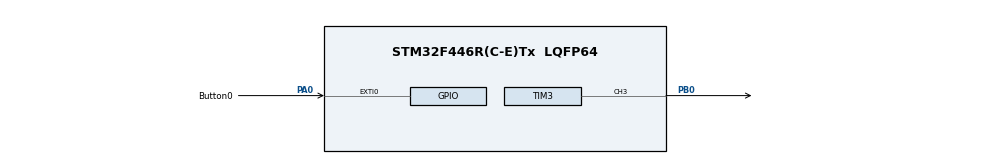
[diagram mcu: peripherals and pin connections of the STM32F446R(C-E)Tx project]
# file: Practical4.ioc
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Dma.Request0=TIM2_CH1
Dma.TIM2_CH1.0.Direction=DMA_PERIPH_TO_MEMORY
Dma.TIM2_CH1.0.FIFOMode=DMA_FIFOMODE_DISABLE
Dma.TIM2_CH1.0.Instance=DMA1_Stream5
Dma.TIM2_CH1.0.MemDataAlignment=DMA_MDATAALIGN_WORD
Dma.TIM2_CH1.0.MemInc=DMA_MINC_ENABLE
Dma.TIM2_CH1.0.Mode=DMA_NORMAL
Dma.TIM2_CH1.0.PeriphDataAlignment=DMA_PDATAALIGN_WORD
Dma.TIM2_CH1.0.PeriphInc=DMA_PINC_DISABLE
Dma.TIM2_CH1.0.Priority=DMA_PRIORITY_LOW
Mcu.Family=STM32F4
Mcu.Name=STM32F446R(C-E)Tx
Mcu.Package=LQFP64
NVIC.DMA1_Stream5_IRQn=true\:0\:0\:false\:false\:true\:false\:true\:true
NVIC.PriorityGroup=NVIC_PRIORITYGROUP_4
PA0-WKUP.GPIO_Label=Button0
PA0-WKUP.Signal=GPXTI0
PB0.Signal=S_TIM3_CH3
PH0-OSC_IN.Mode=HSE-External-Oscillator
PH0-OSC_IN.Signal=RCC_OSC_IN
PH1-OSC_OUT.Mode=HSE-External-Oscillator
PH1-OSC_OUT.Signal=RCC_OSC_OUT
ProjectManager.HeapSize=0x200
ProjectManager.StackSize=0x400
ProjectManager.TargetToolchain=STM32CubeIDE
RCC.CortexFreq_Value=16000000
RCC.USBFreq_Value=96000000
RCC.VCOOutputFreq_Value=192000000
SH.S_TIM3_CH3.0=TIM3_CH3,PWM Generation3 CH3
TIM2.Channel-Output\ Compare1\ No\ Output=TIM_CHANNEL_1
TIM3.Channel-PWM\ Generation3\ CH3=TIM_CHANNEL_3
TIM3.Period=159
VP_TIM2_VS_ClockSourceINT.Mode=Internal
VP_TIM2_VS_no_output1.Mode=Output Compare1 No Output
VP_TIM3_VS_ClockSourceINT.Mode=Internal
board=custom

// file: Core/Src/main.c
/* USER CODE BEGIN Header */
/**
  ******************************************************************************
  * @file           : main.c
  * @brief          : Main program body
  ******************************************************************************
  * @attention
  *
  * Copyright (c) 2025 STMicroelectronics.
  * All rights reserved.
  *
  * This software is licensed under terms that can be found in the LICENSE file
  * in the root directory of this software component.
  * If no LICENSE file comes with this software, it is provided AS-IS.
  *
  ******************************************************************************
  */
/* USER CODE END Header */
#include "main.h"

/* USER CODE BEGIN Includes */
#include <stdio.h>
#include <stdint.h>
#include "stm32f4xx.h"
#include "lcd_stm32f4.h"

//INCLUDE LUTS

//Following three have 75000 samples from their respective .wav audio file.
//So when playing back the samples, to effectively reproduce the original file the play back frequency should be (selected samples)/(total file samples) * sampling_freq

//Drum.wav Duration       : 00:00:11.34 = 499968 samples
#include "drum.inc"

//Guitar.wav Duration       : 00:00:10.58 = 466560 samples = 793.469 CDDA sector
#include "guitar.inc"

//Piano.wav Duration       : 00:00:18.86 = 831744 samples = 1414.53 CDDA sectors
#include "piano.inc"

//Following three have 128 samples, we will play them back at 500Hz, meaning a play back sample rate of 64kHz.
#include "saw.inc"
#include "sine.inc"
#include "triangle.inc"

/* USER CODE END Includes */

/* USER CODE BEGIN PD */
// TODO: Add values for below variables
//#define NS 256   // Number of samples in LUT
#define TIM2CLK 16000000 // STM Clock frequency: Hint You might want to check the ioc file
 //#define F_SIGNAL 1	// Frequency of output analog signal#define WAVEFORM_COUNT 6
#define WAVEFORM_COUNT 6
#define LCD_CLEAR_DISPLAY 0x01

/* USER CODE END PD */

TIM_HandleTypeDef htim2;
TIM_HandleTypeDef htim3;
DMA_HandleTypeDef hdma_tim2_ch1;

/* USER CODE BEGIN PV */
// TODO: Add code for global variables, including LUTs

uint16_t lastPress = 0;

const uint16_t debounceDelay = 200;

const char* waveformNames[] = {
    "Sine",
    "Sawtooth",
    "Triangular",
    "Piano",
    "Guitar",
    "Drum"
};

/* USER CODE BEGIN PTD */
typedef enum {
    SINE = 0,
    SAWTOOTH,
    TRIANGULAR,
    PIANO,
    GUITAR,
    DRUM
} WaveType;
WaveType currentWave = SINE;
/* USER CODE END PTD */
float F_SIGNAL[WAVEFORM_COUNT];

//triangle, sine, saw, piano, guitar, drum
const uint32_t NS_values[] = {256, 256, 256, 75000, 75000, 75000};
const* waveforms[] = {"Triangle", "Sine", "Saw", "Piano", "Guitar", "Drum"};

const uint32_t NS[WAVEFORM_COUNT] = {
    256,
    256,
    256,
	40000,
	40000,
	40000};

uint32_t TIM2_Ticks[WAVEFORM_COUNT];

// TODO: Equation to calculate TIM2_Ticks

uint32_t DestAddress = (uint32_t) &(TIM3->CCR3); // Write LUT TO TIM3->CCR3 to modify PWM duty cycle

/* USER CODE END PV */

void SystemClock_Config(void);
static void MX_GPIO_Init(void);
static void MX_DMA_Init(void);
static void MX_TIM2_Init(void);
static void MX_TIM3_Init(void);
/* USER CODE BEGIN PFP */
void EXTI0_IRQHandler(void);
/* USER CODE END PFP */

/* USER CODE BEGIN 0 */

//The play back frequency of the chosen audio track
uint16_t calcFSignal(uint32_t selected_sample_size, uint32_t original_file_size);

void initFSignal(void) {
    F_SIGNAL[SINE] = 2000;
    F_SIGNAL[SAWTOOTH] = 500;
    F_SIGNAL[TRIANGULAR] = 500;
    F_SIGNAL[PIANO] = 0.05;
    F_SIGNAL[GUITAR] = 0.1;
    F_SIGNAL[DRUM] = 0.1;
}

/* USER CODE END 0 */

int main(void)
{

  /* MCU Configuration--------------------------------------------------------*/

  /* Reset of all peripherals, Initializes the Flash interface and the Systick. */
  HAL_Init();
  initFSignal();
  /* USER CODE BEGIN Init */
  for(int i = 0; i < WAVEFORM_COUNT; i++) {
          TIM2_Ticks[i] = (uint32_t)(TIM2CLK / (F_SIGNAL[i] * NS[i]));
  }
  /* USER CODE END Init */

  /* Configure the system clock */
  SystemClock_Config();

  /* Initialize all configured peripherals */
  MX_GPIO_Init();
  MX_DMA_Init();
  MX_TIM2_Init();
  MX_TIM3_Init();
  /* USER CODE BEGIN 2 */
  // TODO: Start TIM3 in PWM mode on channel 3
  HAL_TIM_PWM_Start(&htim3, TIM_CHANNEL_3);

  // TODO: Start TIM2 in Output Compare (OC) mode on channel 1
  HAL_TIM_OC_Start(&htim2, TIM_CHANNEL_1);

  // TODO: Start DMA in IT mode on TIM2->CH1. Source is LUT and Dest is TIM3->CCR3; start with Sine LUT
  TIM2->ARR = TIM2_Ticks[currentWave];
  HAL_TIM_OC_Start(&htim2, TIM_CHANNEL_1);
  HAL_DMA_Start_IT(&hdma_tim2_ch1,(uint32_t)Sine_LUT, DestAddress, NS[currentWave]);
  // TODO: Write current waveform to LCD(Sine is the first waveform)
  	init_LCD();
  	lcd_putstring(waveformNames[currentWave]);

  // TODO: Enable DMA (start transfer from LUT to CCR)
  __HAL_TIM_ENABLE_DMA(&htim2, TIM_DMA_CC1);
  /* USER CODE END 2 */

  /* Infinite loop */
  while (1)
  {
    /* USER CODE END WHILE */

  }

}

void SystemClock_Config(void)
{
  RCC_OscInitTypeDef RCC_OscInitStruct = {0};
  RCC_ClkInitTypeDef RCC_ClkInitStruct = {0};

  /** Configure the main internal regulator output voltage
  */
  __HAL_RCC_PWR_CLK_ENABLE();
  __HAL_PWR_VOLTAGESCALING_CONFIG(PWR_REGULATOR_VOLTAGE_SCALE3);

  /** Initializes the RCC Oscillators according to the specified parameters
  * in the RCC_OscInitTypeDef structure.
  */
  RCC_OscInitStruct.OscillatorType = RCC_OSCILLATORTYPE_HSI;
  RCC_OscInitStruct.HSIState = RCC_HSI_ON;
  RCC_OscInitStruct.HSICalibrationValue = RCC_HSICALIBRATION_DEFAULT;
  RCC_OscInitStruct.PLL.PLLState = RCC_PLL_NONE;
  if (HAL_RCC_OscConfig(&RCC_OscInitStruct) != HAL_OK)
  {
    Error_Handler();
  }

  /** Initializes the CPU, AHB and APB buses clocks
  */
  RCC_ClkInitStruct.ClockType = RCC_CLOCKTYPE_HCLK|RCC_CLOCKTYPE_SYSCLK
                              |RCC_CLOCKTYPE_PCLK1|RCC_CLOCKTYPE_PCLK2;
  RCC_ClkInitStruct.SYSCLKSource = RCC_SYSCLKSOURCE_HSI;
  RCC_ClkInitStruct.AHBCLKDivider = RCC_SYSCLK_DIV1;
  RCC_ClkInitStruct.APB1CLKDivider = RCC_HCLK_DIV1;
  RCC_ClkInitStruct.APB2CLKDivider = RCC_HCLK_DIV1;

  if (HAL_RCC_ClockConfig(&RCC_ClkInitStruct, FLASH_LATENCY_0) != HAL_OK)
  {
    Error_Handler();
  }
}

static void MX_TIM2_Init(void)
{

  TIM_ClockConfigTypeDef sClockSourceConfig = {0};
  TIM_MasterConfigTypeDef sMasterConfig = {0};
  TIM_OC_InitTypeDef sConfigOC = {0};

  htim2.Instance = TIM2;
  htim2.Init.Prescaler = 0;
  htim2.Init.CounterMode = TIM_COUNTERMODE_UP;
  htim2.Init.Period = 4294967295;
  htim2.Init.ClockDivision = TIM_CLOCKDIVISION_DIV1;
  htim2.Init.AutoReloadPreload = TIM_AUTORELOAD_PRELOAD_DISABLE;
  if (HAL_TIM_Base_Init(&htim2) != HAL_OK)
  {
    Error_Handler();
  }
  sClockSourceConfig.ClockSource = TIM_CLOCKSOURCE_INTERNAL;
  if (HAL_TIM_ConfigClockSource(&htim2, &sClockSourceConfig) != HAL_OK)
  {
    Error_Handler();
  }
  if (HAL_TIM_OC_Init(&htim2) != HAL_OK)
  {
    Error_Handler();
  }
  sMasterConfig.MasterOutputTrigger = TIM_TRGO_RESET;
  sMasterConfig.MasterSlaveMode = TIM_MASTERSLAVEMODE_DISABLE;
  if (HAL_TIMEx_MasterConfigSynchronization(&htim2, &sMasterConfig) != HAL_OK)
  {
    Error_Handler();
  }
  sConfigOC.OCMode = TIM_OCMODE_TIMING;
  sConfigOC.Pulse = 0;
  sConfigOC.OCPolarity = TIM_OCPOLARITY_HIGH;
  sConfigOC.OCFastMode = TIM_OCFAST_DISABLE;
  if (HAL_TIM_OC_ConfigChannel(&htim2, &sConfigOC, TIM_CHANNEL_1) != HAL_OK)
  {
    Error_Handler();
  }
  /* USER CODE BEGIN TIM2_Init 2 */
  /* TIM2_CH1 DMA Init */
  __HAL_RCC_DMA1_CLK_ENABLE();

  hdma_tim2_ch1.Instance = DMA1_Stream5;
  hdma_tim2_ch1.Init.Channel = DMA_CHANNEL_3;         // TIM2_CH1 is on channel 3
  hdma_tim2_ch1.Init.Direction = DMA_MEMORY_TO_PERIPH; // Memory -> TIM3->CCR3
  hdma_tim2_ch1.Init.PeriphInc = DMA_PINC_DISABLE;    // Peripheral address fixed
  hdma_tim2_ch1.Init.MemInc = DMA_MINC_ENABLE;        // Memory address increments
  hdma_tim2_ch1.Init.PeriphDataAlignment = DMA_PDATAALIGN_HALFWORD;  // Changed from WORD
  hdma_tim2_ch1.Init.MemDataAlignment = DMA_MDATAALIGN_HALFWORD;
  hdma_tim2_ch1.Init.Mode = DMA_CIRCULAR;            // Repeat LUT automatically
  hdma_tim2_ch1.Init.Priority = DMA_PRIORITY_HIGH;
  hdma_tim2_ch1.Init.FIFOMode = DMA_FIFOMODE_DISABLE;

  if (HAL_DMA_Init(&hdma_tim2_ch1) != HAL_OK)
  {
      Error_Handler();
  }

  /* Link DMA handle to TIM2 handle */
  __HAL_LINKDMA(&htim2, hdma[TIM_DMA_ID_CC1], hdma_tim2_ch1);
  /* USER CODE END TIM2_Init 2 */

}

static void MX_TIM3_Init(void)
{

  TIM_ClockConfigTypeDef sClockSourceConfig = {0};
  TIM_MasterConfigTypeDef sMasterConfig = {0};
  TIM_OC_InitTypeDef sConfigOC = {0};

  htim3.Instance = TIM3;
  htim3.Init.Prescaler = 0;
  htim3.Init.CounterMode = TIM_COUNTERMODE_UP;
  htim3.Init.Period = 399;
  htim3.Init.ClockDivision = TIM_CLOCKDIVISION_DIV1;
  htim3.Init.AutoReloadPreload = TIM_AUTORELOAD_PRELOAD_DISABLE;
  if (HAL_TIM_Base_Init(&htim3) != HAL_OK)
  {
    Error_Handler();
  }
  sClockSourceConfig.ClockSource = TIM_CLOCKSOURCE_INTERNAL;
  if (HAL_TIM_ConfigClockSource(&htim3, &sClockSourceConfig) != HAL_OK)
  {
    Error_Handler();
  }
  if (HAL_TIM_PWM_Init(&htim3) != HAL_OK)
  {
    Error_Handler();
  }
  sMasterConfig.MasterOutputTrigger = TIM_TRGO_RESET;
  sMasterConfig.MasterSlaveMode = TIM_MASTERSLAVEMODE_DISABLE;
  if (HAL_TIMEx_MasterConfigSynchronization(&htim3, &sMasterConfig) != HAL_OK)
  {
    Error_Handler();
  }
  sConfigOC.OCMode = TIM_OCMODE_PWM1;
  sConfigOC.Pulse = 200;
  sConfigOC.OCPolarity = TIM_OCPOLARITY_HIGH;
  sConfigOC.OCFastMode = TIM_OCFAST_DISABLE;
  if (HAL_TIM_PWM_ConfigChannel(&htim3, &sConfigOC, TIM_CHANNEL_3) != HAL_OK)
  {
    Error_Handler();
  }
  HAL_TIM_MspPostInit(&htim3);

}

static void MX_DMA_Init(void)
{

  /* DMA controller clock enable */
  __HAL_RCC_DMA1_CLK_ENABLE();

  /* DMA interrupt init */
  /* DMA1_Stream5_IRQn interrupt configuration */
  HAL_NVIC_SetPriority(DMA1_Stream5_IRQn, 0, 0);
  HAL_NVIC_EnableIRQ(DMA1_Stream5_IRQn);

}

static void MX_GPIO_Init(void)
{
  GPIO_InitTypeDef GPIO_InitStruct = {0};

  /* GPIO Ports Clock Enable */
  __HAL_RCC_GPIOH_CLK_ENABLE();
  __HAL_RCC_GPIOA_CLK_ENABLE();
  __HAL_RCC_GPIOB_CLK_ENABLE();

  // -------------------------------
  // LCD pins configuration
  // -------------------------------
  // Configure PC14 (RS) and PC15 (E) as output push-pull
  GPIO_InitStruct.Pin = GPIO_PIN_14 | GPIO_PIN_15;
  GPIO_InitStruct.Mode = GPIO_MODE_OUTPUT_PP;
  GPIO_InitStruct.Pull = GPIO_NOPULL;
  GPIO_InitStruct.Speed = GPIO_SPEED_FREQ_LOW;
  HAL_GPIO_Init(GPIOC, &GPIO_InitStruct);

  // Configure PB8 (D4) and PB9 (D5) as output push-pull
  GPIO_InitStruct.Pin = GPIO_PIN_8 | GPIO_PIN_9;
  HAL_GPIO_Init(GPIOB, &GPIO_InitStruct);

  // Configure PA12 (D6) and PA15 (D7) as output push-pull
  GPIO_InitStruct.Pin = GPIO_PIN_12 | GPIO_PIN_15;
  HAL_GPIO_Init(GPIOA, &GPIO_InitStruct);

  // Set all LCD pins LOW initially
  HAL_GPIO_WritePin(GPIOC, GPIO_PIN_14 | GPIO_PIN_15, GPIO_PIN_RESET);
  HAL_GPIO_WritePin(GPIOB, GPIO_PIN_8 | GPIO_PIN_9, GPIO_PIN_RESET);
  HAL_GPIO_WritePin(GPIOA, GPIO_PIN_12 | GPIO_PIN_15, GPIO_PIN_RESET);

  // -------------------------------
  // Button0 configuration (PA0)
  // -------------------------------
  GPIO_InitStruct.Pin = Button0_Pin;
  GPIO_InitStruct.Mode = GPIO_MODE_IT_RISING; // Interrupt on rising edge
  GPIO_InitStruct.Pull = GPIO_PULLUP;         // Use pull-up resistor
  HAL_GPIO_Init(GPIOA, &GPIO_InitStruct);

  // Enable and set EXTI line 0 interrupt priority
  HAL_NVIC_SetPriority(EXTI0_IRQn, 2, 0);
  HAL_NVIC_EnableIRQ(EXTI0_IRQn);

  /* USER CODE END MX_GPIO_Init_2 */
}

/* USER CODE BEGIN 4 */
void EXTI0_IRQHandler(void){

	// TODO: Debounce using HAL_GetTick()
	uint32_t currentTime = HAL_GetTick();

	// TODO: Disable DMA transfer and abort IT, then start DMA in IT mode with new LUT and re-enable transfer
	// HINT: Consider using C's "switch" function to handle LUT changes
	if ((currentTime - lastPress) > debounceDelay)
	    {
	        // Update lastButtonPress with current time
	        lastPress = currentTime;

	        __HAL_TIM_DISABLE_DMA(&htim2, TIM_DMA_CC1);
	                HAL_DMA_Abort_IT(&hdma_tim2_ch1);

	                currentWave = (WaveType)((currentWave + 1) % WAVEFORM_COUNT);

	                TIM2->ARR = TIM2_Ticks[currentWave];

	                switch(currentWave)
	                {
	                    case SINE:
	                        HAL_DMA_Start_IT(&hdma_tim2_ch1, (uint32_t)Sine_LUT, DestAddress, NS[currentWave]);
	                        break;
	                    case SAWTOOTH:
	                        HAL_DMA_Start_IT(&hdma_tim2_ch1, (uint32_t)Saw_LUT, DestAddress, NS[currentWave]);
	                        break;
	                    case TRIANGULAR:
	                        HAL_DMA_Start_IT(&hdma_tim2_ch1, (uint32_t)Triangle_LUT, DestAddress, NS[currentWave]);
	                        break;
	                    case PIANO:
	                        HAL_DMA_Start_IT(&hdma_tim2_ch1, (uint32_t)piano, DestAddress, NS[currentWave]);
	                        break;
	                    case GUITAR:
	                        HAL_DMA_Start_IT(&hdma_tim2_ch1, (uint32_t)guitar, DestAddress, NS[currentWave]);
	                        break;
	                    case DRUM:
	                        HAL_DMA_Start_IT(&hdma_tim2_ch1, (uint32_t)drum, DestAddress, NS[currentWave]);
	                        break;
	                }
	                lcd_command(LCD_CLEAR_DISPLAY);
	                // Update LCD
	                lcd_putstring(waveformNames[currentWave]);

	                // Restart DMA
	                __HAL_TIM_ENABLE_DMA(&htim2, TIM_DMA_CC1);
	            }

	            HAL_GPIO_EXTI_IRQHandler(Button0_Pin);
	        }

/* USER CODE END 4 */

void Error_Handler(void)
{
  __disable_irq();
  while (1)
  {
  }
}
